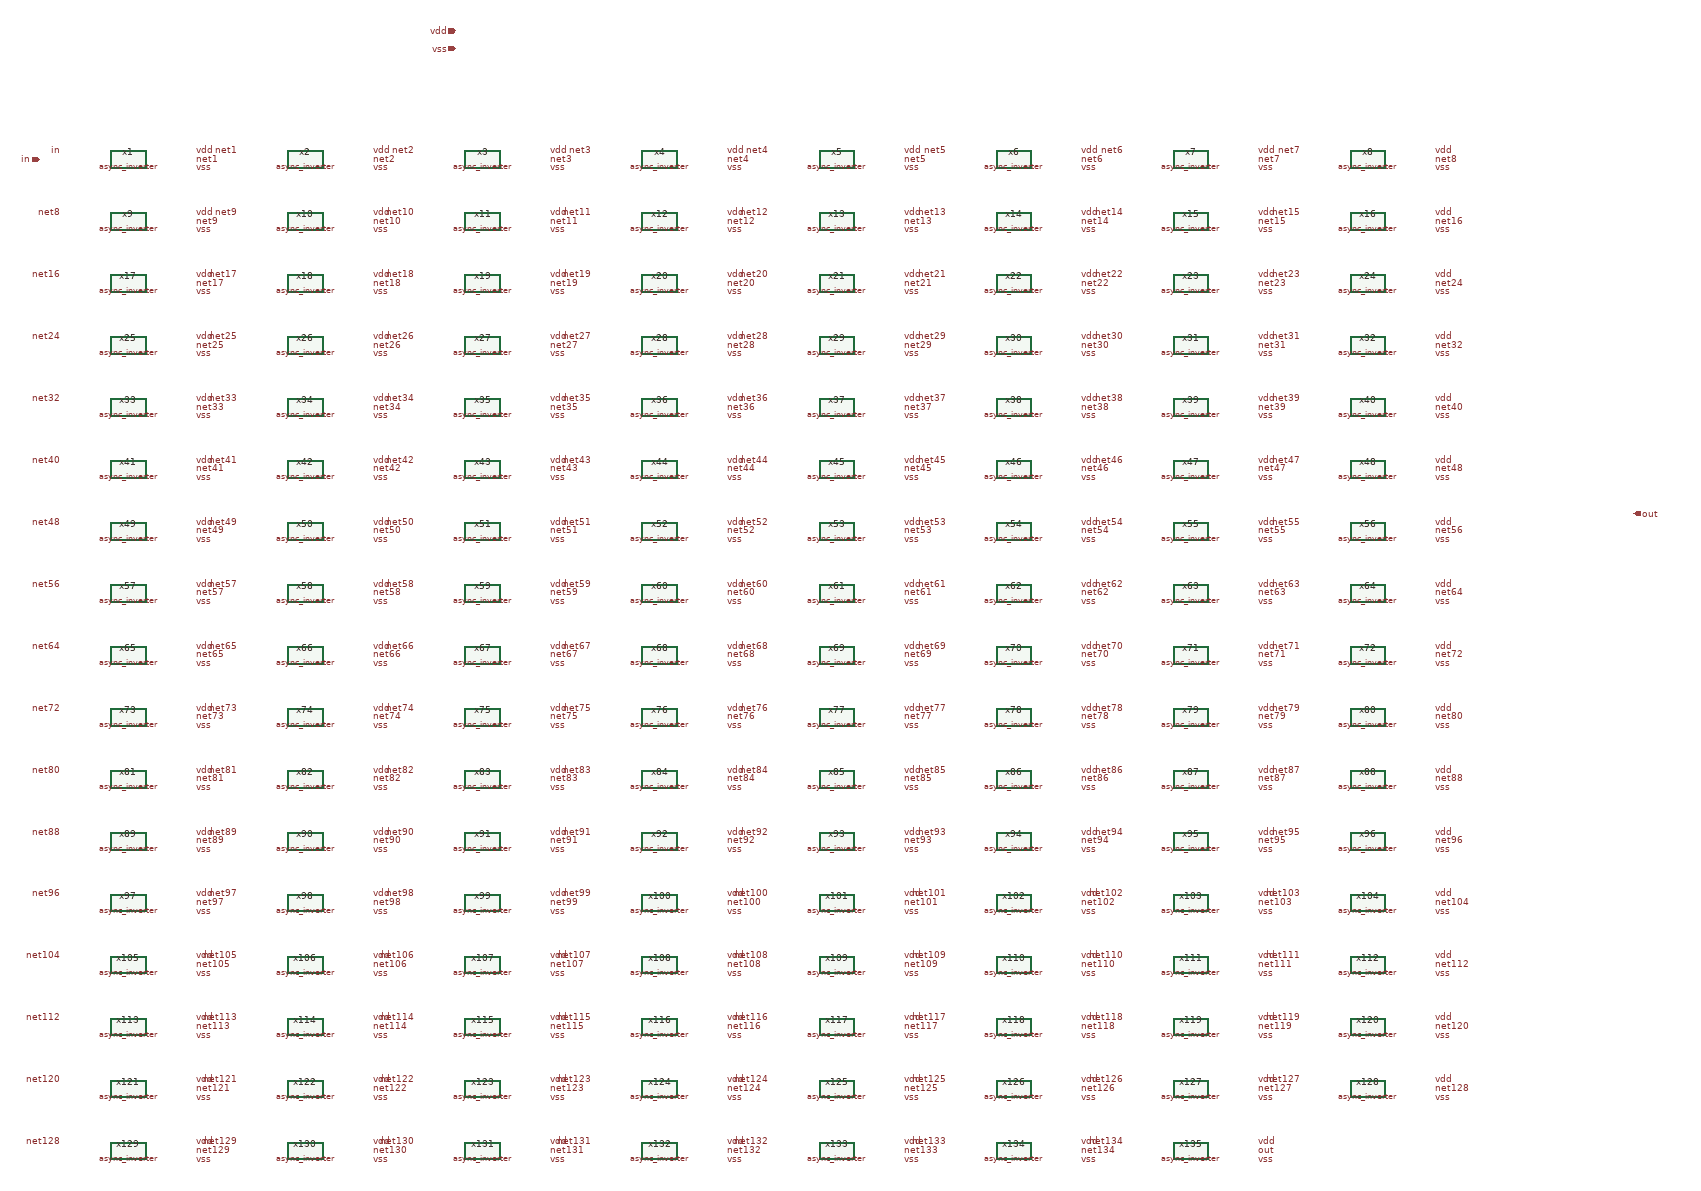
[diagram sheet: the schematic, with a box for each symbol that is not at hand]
v {xschem version=3.4.8RC file_version=1.3}
G {}
K {}
V {}
S {}
F {}
E {}
C {ipin.sym} -1600 -400 0 0 {name=p_in lab=in}
C {iopin.sym} -660 -690 0 0 {name=p_vdd lab=vdd}
C {iopin.sym} -660 -650 0 0 {name=p_vss lab=vss}
C {opin.sym} 2000 400 0 0 {name=p_out lab=out}
C {sar_adc/blocks/async_sar/async_inverter.sym} -1400 -400 0 0 {name=x1}
C {lab_wire.sym} -1550 -420 0 0 {name=l_x1_in lab=in}
C {lab_wire.sym} -1250 -400 2 0 {name=l_x1_out lab=net1}
C {lab_wire.sym} -1250 -420 2 0 {name=l_x1_vdd lab=vdd}
C {lab_wire.sym} -1250 -380 2 0 {name=l_x1_vss lab=vss}
C {sar_adc/blocks/async_sar/async_inverter.sym} -1000 -400 0 0 {name=x2}
C {lab_wire.sym} -1150 -420 0 0 {name=l_x2_in lab=net1}
C {lab_wire.sym} -850 -400 2 0 {name=l_x2_out lab=net2}
C {lab_wire.sym} -850 -420 2 0 {name=l_x2_vdd lab=vdd}
C {lab_wire.sym} -850 -380 2 0 {name=l_x2_vss lab=vss}
C {sar_adc/blocks/async_sar/async_inverter.sym} -600 -400 0 0 {name=x3}
C {lab_wire.sym} -750 -420 0 0 {name=l_x3_in lab=net2}
C {lab_wire.sym} -450 -400 2 0 {name=l_x3_out lab=net3}
C {lab_wire.sym} -450 -420 2 0 {name=l_x3_vdd lab=vdd}
C {lab_wire.sym} -450 -380 2 0 {name=l_x3_vss lab=vss}
C {sar_adc/blocks/async_sar/async_inverter.sym} -200 -400 0 0 {name=x4}
C {lab_wire.sym} -350 -420 0 0 {name=l_x4_in lab=net3}
C {lab_wire.sym} -50 -400 2 0 {name=l_x4_out lab=net4}
C {lab_wire.sym} -50 -420 2 0 {name=l_x4_vdd lab=vdd}
C {lab_wire.sym} -50 -380 2 0 {name=l_x4_vss lab=vss}
C {sar_adc/blocks/async_sar/async_inverter.sym} 200 -400 0 0 {name=x5}
C {lab_wire.sym} 50 -420 0 0 {name=l_x5_in lab=net4}
C {lab_wire.sym} 350 -400 2 0 {name=l_x5_out lab=net5}
C {lab_wire.sym} 350 -420 2 0 {name=l_x5_vdd lab=vdd}
C {lab_wire.sym} 350 -380 2 0 {name=l_x5_vss lab=vss}
C {sar_adc/blocks/async_sar/async_inverter.sym} 600 -400 0 0 {name=x6}
C {lab_wire.sym} 450 -420 0 0 {name=l_x6_in lab=net5}
C {lab_wire.sym} 750 -400 2 0 {name=l_x6_out lab=net6}
C {lab_wire.sym} 750 -420 2 0 {name=l_x6_vdd lab=vdd}
C {lab_wire.sym} 750 -380 2 0 {name=l_x6_vss lab=vss}
C {sar_adc/blocks/async_sar/async_inverter.sym} 1000 -400 0 0 {name=x7}
C {lab_wire.sym} 850 -420 0 0 {name=l_x7_in lab=net6}
C {lab_wire.sym} 1150 -400 2 0 {name=l_x7_out lab=net7}
C {lab_wire.sym} 1150 -420 2 0 {name=l_x7_vdd lab=vdd}
C {lab_wire.sym} 1150 -380 2 0 {name=l_x7_vss lab=vss}
C {sar_adc/blocks/async_sar/async_inverter.sym} 1400 -400 0 0 {name=x8}
C {lab_wire.sym} 1250 -420 0 0 {name=l_x8_in lab=net7}
C {lab_wire.sym} 1550 -400 2 0 {name=l_x8_out lab=net8}
C {lab_wire.sym} 1550 -420 2 0 {name=l_x8_vdd lab=vdd}
C {lab_wire.sym} 1550 -380 2 0 {name=l_x8_vss lab=vss}
C {sar_adc/blocks/async_sar/async_inverter.sym} -1400 -260 0 0 {name=x9}
C {lab_wire.sym} -1550 -280 0 0 {name=l_x9_in lab=net8}
C {lab_wire.sym} -1250 -260 2 0 {name=l_x9_out lab=net9}
C {lab_wire.sym} -1250 -280 2 0 {name=l_x9_vdd lab=vdd}
C {lab_wire.sym} -1250 -240 2 0 {name=l_x9_vss lab=vss}
C {sar_adc/blocks/async_sar/async_inverter.sym} -1000 -260 0 0 {name=x10}
C {lab_wire.sym} -1150 -280 0 0 {name=l_x10_in lab=net9}
C {lab_wire.sym} -850 -260 2 0 {name=l_x10_out lab=net10}
C {lab_wire.sym} -850 -280 2 0 {name=l_x10_vdd lab=vdd}
C {lab_wire.sym} -850 -240 2 0 {name=l_x10_vss lab=vss}
C {sar_adc/blocks/async_sar/async_inverter.sym} -600 -260 0 0 {name=x11}
C {lab_wire.sym} -750 -280 0 0 {name=l_x11_in lab=net10}
C {lab_wire.sym} -450 -260 2 0 {name=l_x11_out lab=net11}
C {lab_wire.sym} -450 -280 2 0 {name=l_x11_vdd lab=vdd}
C {lab_wire.sym} -450 -240 2 0 {name=l_x11_vss lab=vss}
C {sar_adc/blocks/async_sar/async_inverter.sym} -200 -260 0 0 {name=x12}
C {lab_wire.sym} -350 -280 0 0 {name=l_x12_in lab=net11}
C {lab_wire.sym} -50 -260 2 0 {name=l_x12_out lab=net12}
C {lab_wire.sym} -50 -280 2 0 {name=l_x12_vdd lab=vdd}
C {lab_wire.sym} -50 -240 2 0 {name=l_x12_vss lab=vss}
C {sar_adc/blocks/async_sar/async_inverter.sym} 200 -260 0 0 {name=x13}
C {lab_wire.sym} 50 -280 0 0 {name=l_x13_in lab=net12}
C {lab_wire.sym} 350 -260 2 0 {name=l_x13_out lab=net13}
C {lab_wire.sym} 350 -280 2 0 {name=l_x13_vdd lab=vdd}
C {lab_wire.sym} 350 -240 2 0 {name=l_x13_vss lab=vss}
C {sar_adc/blocks/async_sar/async_inverter.sym} 600 -260 0 0 {name=x14}
C {lab_wire.sym} 450 -280 0 0 {name=l_x14_in lab=net13}
C {lab_wire.sym} 750 -260 2 0 {name=l_x14_out lab=net14}
C {lab_wire.sym} 750 -280 2 0 {name=l_x14_vdd lab=vdd}
C {lab_wire.sym} 750 -240 2 0 {name=l_x14_vss lab=vss}
C {sar_adc/blocks/async_sar/async_inverter.sym} 1000 -260 0 0 {name=x15}
C {lab_wire.sym} 850 -280 0 0 {name=l_x15_in lab=net14}
C {lab_wire.sym} 1150 -260 2 0 {name=l_x15_out lab=net15}
C {lab_wire.sym} 1150 -280 2 0 {name=l_x15_vdd lab=vdd}
C {lab_wire.sym} 1150 -240 2 0 {name=l_x15_vss lab=vss}
C {sar_adc/blocks/async_sar/async_inverter.sym} 1400 -260 0 0 {name=x16}
C {lab_wire.sym} 1250 -280 0 0 {name=l_x16_in lab=net15}
C {lab_wire.sym} 1550 -260 2 0 {name=l_x16_out lab=net16}
C {lab_wire.sym} 1550 -280 2 0 {name=l_x16_vdd lab=vdd}
C {lab_wire.sym} 1550 -240 2 0 {name=l_x16_vss lab=vss}
C {sar_adc/blocks/async_sar/async_inverter.sym} -1400 -120 0 0 {name=x17}
C {lab_wire.sym} -1550 -140 0 0 {name=l_x17_in lab=net16}
C {lab_wire.sym} -1250 -120 2 0 {name=l_x17_out lab=net17}
C {lab_wire.sym} -1250 -140 2 0 {name=l_x17_vdd lab=vdd}
C {lab_wire.sym} -1250 -100 2 0 {name=l_x17_vss lab=vss}
C {sar_adc/blocks/async_sar/async_inverter.sym} -1000 -120 0 0 {name=x18}
C {lab_wire.sym} -1150 -140 0 0 {name=l_x18_in lab=net17}
C {lab_wire.sym} -850 -120 2 0 {name=l_x18_out lab=net18}
C {lab_wire.sym} -850 -140 2 0 {name=l_x18_vdd lab=vdd}
C {lab_wire.sym} -850 -100 2 0 {name=l_x18_vss lab=vss}
C {sar_adc/blocks/async_sar/async_inverter.sym} -600 -120 0 0 {name=x19}
C {lab_wire.sym} -750 -140 0 0 {name=l_x19_in lab=net18}
C {lab_wire.sym} -450 -120 2 0 {name=l_x19_out lab=net19}
C {lab_wire.sym} -450 -140 2 0 {name=l_x19_vdd lab=vdd}
C {lab_wire.sym} -450 -100 2 0 {name=l_x19_vss lab=vss}
C {sar_adc/blocks/async_sar/async_inverter.sym} -200 -120 0 0 {name=x20}
C {lab_wire.sym} -350 -140 0 0 {name=l_x20_in lab=net19}
C {lab_wire.sym} -50 -120 2 0 {name=l_x20_out lab=net20}
C {lab_wire.sym} -50 -140 2 0 {name=l_x20_vdd lab=vdd}
C {lab_wire.sym} -50 -100 2 0 {name=l_x20_vss lab=vss}
C {sar_adc/blocks/async_sar/async_inverter.sym} 200 -120 0 0 {name=x21}
C {lab_wire.sym} 50 -140 0 0 {name=l_x21_in lab=net20}
C {lab_wire.sym} 350 -120 2 0 {name=l_x21_out lab=net21}
C {lab_wire.sym} 350 -140 2 0 {name=l_x21_vdd lab=vdd}
C {lab_wire.sym} 350 -100 2 0 {name=l_x21_vss lab=vss}
C {sar_adc/blocks/async_sar/async_inverter.sym} 600 -120 0 0 {name=x22}
C {lab_wire.sym} 450 -140 0 0 {name=l_x22_in lab=net21}
C {lab_wire.sym} 750 -120 2 0 {name=l_x22_out lab=net22}
C {lab_wire.sym} 750 -140 2 0 {name=l_x22_vdd lab=vdd}
C {lab_wire.sym} 750 -100 2 0 {name=l_x22_vss lab=vss}
C {sar_adc/blocks/async_sar/async_inverter.sym} 1000 -120 0 0 {name=x23}
C {lab_wire.sym} 850 -140 0 0 {name=l_x23_in lab=net22}
C {lab_wire.sym} 1150 -120 2 0 {name=l_x23_out lab=net23}
C {lab_wire.sym} 1150 -140 2 0 {name=l_x23_vdd lab=vdd}
C {lab_wire.sym} 1150 -100 2 0 {name=l_x23_vss lab=vss}
C {sar_adc/blocks/async_sar/async_inverter.sym} 1400 -120 0 0 {name=x24}
C {lab_wire.sym} 1250 -140 0 0 {name=l_x24_in lab=net23}
C {lab_wire.sym} 1550 -120 2 0 {name=l_x24_out lab=net24}
C {lab_wire.sym} 1550 -140 2 0 {name=l_x24_vdd lab=vdd}
C {lab_wire.sym} 1550 -100 2 0 {name=l_x24_vss lab=vss}
C {sar_adc/blocks/async_sar/async_inverter.sym} -1400 20 0 0 {name=x25}
C {lab_wire.sym} -1550 0 0 0 {name=l_x25_in lab=net24}
C {lab_wire.sym} -1250 20 2 0 {name=l_x25_out lab=net25}
C {lab_wire.sym} -1250 0 2 0 {name=l_x25_vdd lab=vdd}
C {lab_wire.sym} -1250 40 2 0 {name=l_x25_vss lab=vss}
C {sar_adc/blocks/async_sar/async_inverter.sym} -1000 20 0 0 {name=x26}
C {lab_wire.sym} -1150 0 0 0 {name=l_x26_in lab=net25}
C {lab_wire.sym} -850 20 2 0 {name=l_x26_out lab=net26}
C {lab_wire.sym} -850 0 2 0 {name=l_x26_vdd lab=vdd}
C {lab_wire.sym} -850 40 2 0 {name=l_x26_vss lab=vss}
C {sar_adc/blocks/async_sar/async_inverter.sym} -600 20 0 0 {name=x27}
C {lab_wire.sym} -750 0 0 0 {name=l_x27_in lab=net26}
C {lab_wire.sym} -450 20 2 0 {name=l_x27_out lab=net27}
C {lab_wire.sym} -450 0 2 0 {name=l_x27_vdd lab=vdd}
C {lab_wire.sym} -450 40 2 0 {name=l_x27_vss lab=vss}
C {sar_adc/blocks/async_sar/async_inverter.sym} -200 20 0 0 {name=x28}
C {lab_wire.sym} -350 0 0 0 {name=l_x28_in lab=net27}
C {lab_wire.sym} -50 20 2 0 {name=l_x28_out lab=net28}
C {lab_wire.sym} -50 0 2 0 {name=l_x28_vdd lab=vdd}
C {lab_wire.sym} -50 40 2 0 {name=l_x28_vss lab=vss}
C {sar_adc/blocks/async_sar/async_inverter.sym} 200 20 0 0 {name=x29}
C {lab_wire.sym} 50 0 0 0 {name=l_x29_in lab=net28}
C {lab_wire.sym} 350 20 2 0 {name=l_x29_out lab=net29}
C {lab_wire.sym} 350 0 2 0 {name=l_x29_vdd lab=vdd}
C {lab_wire.sym} 350 40 2 0 {name=l_x29_vss lab=vss}
C {sar_adc/blocks/async_sar/async_inverter.sym} 600 20 0 0 {name=x30}
C {lab_wire.sym} 450 0 0 0 {name=l_x30_in lab=net29}
C {lab_wire.sym} 750 20 2 0 {name=l_x30_out lab=net30}
C {lab_wire.sym} 750 0 2 0 {name=l_x30_vdd lab=vdd}
C {lab_wire.sym} 750 40 2 0 {name=l_x30_vss lab=vss}
C {sar_adc/blocks/async_sar/async_inverter.sym} 1000 20 0 0 {name=x31}
C {lab_wire.sym} 850 0 0 0 {name=l_x31_in lab=net30}
C {lab_wire.sym} 1150 20 2 0 {name=l_x31_out lab=net31}
C {lab_wire.sym} 1150 0 2 0 {name=l_x31_vdd lab=vdd}
C {lab_wire.sym} 1150 40 2 0 {name=l_x31_vss lab=vss}
C {sar_adc/blocks/async_sar/async_inverter.sym} 1400 20 0 0 {name=x32}
C {lab_wire.sym} 1250 0 0 0 {name=l_x32_in lab=net31}
C {lab_wire.sym} 1550 20 2 0 {name=l_x32_out lab=net32}
C {lab_wire.sym} 1550 0 2 0 {name=l_x32_vdd lab=vdd}
C {lab_wire.sym} 1550 40 2 0 {name=l_x32_vss lab=vss}
C {sar_adc/blocks/async_sar/async_inverter.sym} -1400 160 0 0 {name=x33}
C {lab_wire.sym} -1550 140 0 0 {name=l_x33_in lab=net32}
C {lab_wire.sym} -1250 160 2 0 {name=l_x33_out lab=net33}
C {lab_wire.sym} -1250 140 2 0 {name=l_x33_vdd lab=vdd}
C {lab_wire.sym} -1250 180 2 0 {name=l_x33_vss lab=vss}
C {sar_adc/blocks/async_sar/async_inverter.sym} -1000 160 0 0 {name=x34}
C {lab_wire.sym} -1150 140 0 0 {name=l_x34_in lab=net33}
C {lab_wire.sym} -850 160 2 0 {name=l_x34_out lab=net34}
C {lab_wire.sym} -850 140 2 0 {name=l_x34_vdd lab=vdd}
C {lab_wire.sym} -850 180 2 0 {name=l_x34_vss lab=vss}
C {sar_adc/blocks/async_sar/async_inverter.sym} -600 160 0 0 {name=x35}
C {lab_wire.sym} -750 140 0 0 {name=l_x35_in lab=net34}
C {lab_wire.sym} -450 160 2 0 {name=l_x35_out lab=net35}
C {lab_wire.sym} -450 140 2 0 {name=l_x35_vdd lab=vdd}
C {lab_wire.sym} -450 180 2 0 {name=l_x35_vss lab=vss}
C {sar_adc/blocks/async_sar/async_inverter.sym} -200 160 0 0 {name=x36}
C {lab_wire.sym} -350 140 0 0 {name=l_x36_in lab=net35}
C {lab_wire.sym} -50 160 2 0 {name=l_x36_out lab=net36}
C {lab_wire.sym} -50 140 2 0 {name=l_x36_vdd lab=vdd}
C {lab_wire.sym} -50 180 2 0 {name=l_x36_vss lab=vss}
C {sar_adc/blocks/async_sar/async_inverter.sym} 200 160 0 0 {name=x37}
C {lab_wire.sym} 50 140 0 0 {name=l_x37_in lab=net36}
C {lab_wire.sym} 350 160 2 0 {name=l_x37_out lab=net37}
C {lab_wire.sym} 350 140 2 0 {name=l_x37_vdd lab=vdd}
C {lab_wire.sym} 350 180 2 0 {name=l_x37_vss lab=vss}
C {sar_adc/blocks/async_sar/async_inverter.sym} 600 160 0 0 {name=x38}
C {lab_wire.sym} 450 140 0 0 {name=l_x38_in lab=net37}
C {lab_wire.sym} 750 160 2 0 {name=l_x38_out lab=net38}
C {lab_wire.sym} 750 140 2 0 {name=l_x38_vdd lab=vdd}
C {lab_wire.sym} 750 180 2 0 {name=l_x38_vss lab=vss}
C {sar_adc/blocks/async_sar/async_inverter.sym} 1000 160 0 0 {name=x39}
C {lab_wire.sym} 850 140 0 0 {name=l_x39_in lab=net38}
C {lab_wire.sym} 1150 160 2 0 {name=l_x39_out lab=net39}
C {lab_wire.sym} 1150 140 2 0 {name=l_x39_vdd lab=vdd}
C {lab_wire.sym} 1150 180 2 0 {name=l_x39_vss lab=vss}
C {sar_adc/blocks/async_sar/async_inverter.sym} 1400 160 0 0 {name=x40}
C {lab_wire.sym} 1250 140 0 0 {name=l_x40_in lab=net39}
C {lab_wire.sym} 1550 160 2 0 {name=l_x40_out lab=net40}
C {lab_wire.sym} 1550 140 2 0 {name=l_x40_vdd lab=vdd}
C {lab_wire.sym} 1550 180 2 0 {name=l_x40_vss lab=vss}
C {sar_adc/blocks/async_sar/async_inverter.sym} -1400 300 0 0 {name=x41}
C {lab_wire.sym} -1550 280 0 0 {name=l_x41_in lab=net40}
C {lab_wire.sym} -1250 300 2 0 {name=l_x41_out lab=net41}
C {lab_wire.sym} -1250 280 2 0 {name=l_x41_vdd lab=vdd}
C {lab_wire.sym} -1250 320 2 0 {name=l_x41_vss lab=vss}
C {sar_adc/blocks/async_sar/async_inverter.sym} -1000 300 0 0 {name=x42}
C {lab_wire.sym} -1150 280 0 0 {name=l_x42_in lab=net41}
C {lab_wire.sym} -850 300 2 0 {name=l_x42_out lab=net42}
C {lab_wire.sym} -850 280 2 0 {name=l_x42_vdd lab=vdd}
C {lab_wire.sym} -850 320 2 0 {name=l_x42_vss lab=vss}
C {sar_adc/blocks/async_sar/async_inverter.sym} -600 300 0 0 {name=x43}
C {lab_wire.sym} -750 280 0 0 {name=l_x43_in lab=net42}
C {lab_wire.sym} -450 300 2 0 {name=l_x43_out lab=net43}
C {lab_wire.sym} -450 280 2 0 {name=l_x43_vdd lab=vdd}
C {lab_wire.sym} -450 320 2 0 {name=l_x43_vss lab=vss}
C {sar_adc/blocks/async_sar/async_inverter.sym} -200 300 0 0 {name=x44}
C {lab_wire.sym} -350 280 0 0 {name=l_x44_in lab=net43}
C {lab_wire.sym} -50 300 2 0 {name=l_x44_out lab=net44}
C {lab_wire.sym} -50 280 2 0 {name=l_x44_vdd lab=vdd}
C {lab_wire.sym} -50 320 2 0 {name=l_x44_vss lab=vss}
C {sar_adc/blocks/async_sar/async_inverter.sym} 200 300 0 0 {name=x45}
C {lab_wire.sym} 50 280 0 0 {name=l_x45_in lab=net44}
C {lab_wire.sym} 350 300 2 0 {name=l_x45_out lab=net45}
C {lab_wire.sym} 350 280 2 0 {name=l_x45_vdd lab=vdd}
C {lab_wire.sym} 350 320 2 0 {name=l_x45_vss lab=vss}
C {sar_adc/blocks/async_sar/async_inverter.sym} 600 300 0 0 {name=x46}
C {lab_wire.sym} 450 280 0 0 {name=l_x46_in lab=net45}
C {lab_wire.sym} 750 300 2 0 {name=l_x46_out lab=net46}
C {lab_wire.sym} 750 280 2 0 {name=l_x46_vdd lab=vdd}
C {lab_wire.sym} 750 320 2 0 {name=l_x46_vss lab=vss}
C {sar_adc/blocks/async_sar/async_inverter.sym} 1000 300 0 0 {name=x47}
C {lab_wire.sym} 850 280 0 0 {name=l_x47_in lab=net46}
C {lab_wire.sym} 1150 300 2 0 {name=l_x47_out lab=net47}
C {lab_wire.sym} 1150 280 2 0 {name=l_x47_vdd lab=vdd}
C {lab_wire.sym} 1150 320 2 0 {name=l_x47_vss lab=vss}
C {sar_adc/blocks/async_sar/async_inverter.sym} 1400 300 0 0 {name=x48}
C {lab_wire.sym} 1250 280 0 0 {name=l_x48_in lab=net47}
C {lab_wire.sym} 1550 300 2 0 {name=l_x48_out lab=net48}
C {lab_wire.sym} 1550 280 2 0 {name=l_x48_vdd lab=vdd}
C {lab_wire.sym} 1550 320 2 0 {name=l_x48_vss lab=vss}
C {sar_adc/blocks/async_sar/async_inverter.sym} -1400 440 0 0 {name=x49}
C {lab_wire.sym} -1550 420 0 0 {name=l_x49_in lab=net48}
C {lab_wire.sym} -1250 440 2 0 {name=l_x49_out lab=net49}
C {lab_wire.sym} -1250 420 2 0 {name=l_x49_vdd lab=vdd}
C {lab_wire.sym} -1250 460 2 0 {name=l_x49_vss lab=vss}
C {sar_adc/blocks/async_sar/async_inverter.sym} -1000 440 0 0 {name=x50}
C {lab_wire.sym} -1150 420 0 0 {name=l_x50_in lab=net49}
C {lab_wire.sym} -850 440 2 0 {name=l_x50_out lab=net50}
C {lab_wire.sym} -850 420 2 0 {name=l_x50_vdd lab=vdd}
C {lab_wire.sym} -850 460 2 0 {name=l_x50_vss lab=vss}
C {sar_adc/blocks/async_sar/async_inverter.sym} -600 440 0 0 {name=x51}
C {lab_wire.sym} -750 420 0 0 {name=l_x51_in lab=net50}
C {lab_wire.sym} -450 440 2 0 {name=l_x51_out lab=net51}
C {lab_wire.sym} -450 420 2 0 {name=l_x51_vdd lab=vdd}
C {lab_wire.sym} -450 460 2 0 {name=l_x51_vss lab=vss}
C {sar_adc/blocks/async_sar/async_inverter.sym} -200 440 0 0 {name=x52}
C {lab_wire.sym} -350 420 0 0 {name=l_x52_in lab=net51}
C {lab_wire.sym} -50 440 2 0 {name=l_x52_out lab=net52}
C {lab_wire.sym} -50 420 2 0 {name=l_x52_vdd lab=vdd}
C {lab_wire.sym} -50 460 2 0 {name=l_x52_vss lab=vss}
C {sar_adc/blocks/async_sar/async_inverter.sym} 200 440 0 0 {name=x53}
C {lab_wire.sym} 50 420 0 0 {name=l_x53_in lab=net52}
C {lab_wire.sym} 350 440 2 0 {name=l_x53_out lab=net53}
C {lab_wire.sym} 350 420 2 0 {name=l_x53_vdd lab=vdd}
C {lab_wire.sym} 350 460 2 0 {name=l_x53_vss lab=vss}
C {sar_adc/blocks/async_sar/async_inverter.sym} 600 440 0 0 {name=x54}
C {lab_wire.sym} 450 420 0 0 {name=l_x54_in lab=net53}
C {lab_wire.sym} 750 440 2 0 {name=l_x54_out lab=net54}
C {lab_wire.sym} 750 420 2 0 {name=l_x54_vdd lab=vdd}
C {lab_wire.sym} 750 460 2 0 {name=l_x54_vss lab=vss}
C {sar_adc/blocks/async_sar/async_inverter.sym} 1000 440 0 0 {name=x55}
C {lab_wire.sym} 850 420 0 0 {name=l_x55_in lab=net54}
C {lab_wire.sym} 1150 440 2 0 {name=l_x55_out lab=net55}
C {lab_wire.sym} 1150 420 2 0 {name=l_x55_vdd lab=vdd}
C {lab_wire.sym} 1150 460 2 0 {name=l_x55_vss lab=vss}
C {sar_adc/blocks/async_sar/async_inverter.sym} 1400 440 0 0 {name=x56}
C {lab_wire.sym} 1250 420 0 0 {name=l_x56_in lab=net55}
C {lab_wire.sym} 1550 440 2 0 {name=l_x56_out lab=net56}
C {lab_wire.sym} 1550 420 2 0 {name=l_x56_vdd lab=vdd}
C {lab_wire.sym} 1550 460 2 0 {name=l_x56_vss lab=vss}
C {sar_adc/blocks/async_sar/async_inverter.sym} -1400 580 0 0 {name=x57}
C {lab_wire.sym} -1550 560 0 0 {name=l_x57_in lab=net56}
C {lab_wire.sym} -1250 580 2 0 {name=l_x57_out lab=net57}
C {lab_wire.sym} -1250 560 2 0 {name=l_x57_vdd lab=vdd}
C {lab_wire.sym} -1250 600 2 0 {name=l_x57_vss lab=vss}
C {sar_adc/blocks/async_sar/async_inverter.sym} -1000 580 0 0 {name=x58}
C {lab_wire.sym} -1150 560 0 0 {name=l_x58_in lab=net57}
C {lab_wire.sym} -850 580 2 0 {name=l_x58_out lab=net58}
C {lab_wire.sym} -850 560 2 0 {name=l_x58_vdd lab=vdd}
C {lab_wire.sym} -850 600 2 0 {name=l_x58_vss lab=vss}
C {sar_adc/blocks/async_sar/async_inverter.sym} -600 580 0 0 {name=x59}
C {lab_wire.sym} -750 560 0 0 {name=l_x59_in lab=net58}
C {lab_wire.sym} -450 580 2 0 {name=l_x59_out lab=net59}
C {lab_wire.sym} -450 560 2 0 {name=l_x59_vdd lab=vdd}
C {lab_wire.sym} -450 600 2 0 {name=l_x59_vss lab=vss}
C {sar_adc/blocks/async_sar/async_inverter.sym} -200 580 0 0 {name=x60}
C {lab_wire.sym} -350 560 0 0 {name=l_x60_in lab=net59}
C {lab_wire.sym} -50 580 2 0 {name=l_x60_out lab=net60}
C {lab_wire.sym} -50 560 2 0 {name=l_x60_vdd lab=vdd}
C {lab_wire.sym} -50 600 2 0 {name=l_x60_vss lab=vss}
C {sar_adc/blocks/async_sar/async_inverter.sym} 200 580 0 0 {name=x61}
C {lab_wire.sym} 50 560 0 0 {name=l_x61_in lab=net60}
C {lab_wire.sym} 350 580 2 0 {name=l_x61_out lab=net61}
C {lab_wire.sym} 350 560 2 0 {name=l_x61_vdd lab=vdd}
C {lab_wire.sym} 350 600 2 0 {name=l_x61_vss lab=vss}
C {sar_adc/blocks/async_sar/async_inverter.sym} 600 580 0 0 {name=x62}
C {lab_wire.sym} 450 560 0 0 {name=l_x62_in lab=net61}
C {lab_wire.sym} 750 580 2 0 {name=l_x62_out lab=net62}
C {lab_wire.sym} 750 560 2 0 {name=l_x62_vdd lab=vdd}
C {lab_wire.sym} 750 600 2 0 {name=l_x62_vss lab=vss}
C {sar_adc/blocks/async_sar/async_inverter.sym} 1000 580 0 0 {name=x63}
C {lab_wire.sym} 850 560 0 0 {name=l_x63_in lab=net62}
C {lab_wire.sym} 1150 580 2 0 {name=l_x63_out lab=net63}
C {lab_wire.sym} 1150 560 2 0 {name=l_x63_vdd lab=vdd}
C {lab_wire.sym} 1150 600 2 0 {name=l_x63_vss lab=vss}
C {sar_adc/blocks/async_sar/async_inverter.sym} 1400 580 0 0 {name=x64}
C {lab_wire.sym} 1250 560 0 0 {name=l_x64_in lab=net63}
C {lab_wire.sym} 1550 580 2 0 {name=l_x64_out lab=net64}
C {lab_wire.sym} 1550 560 2 0 {name=l_x64_vdd lab=vdd}
C {lab_wire.sym} 1550 600 2 0 {name=l_x64_vss lab=vss}
C {sar_adc/blocks/async_sar/async_inverter.sym} -1400 720 0 0 {name=x65}
C {lab_wire.sym} -1550 700 0 0 {name=l_x65_in lab=net64}
C {lab_wire.sym} -1250 720 2 0 {name=l_x65_out lab=net65}
C {lab_wire.sym} -1250 700 2 0 {name=l_x65_vdd lab=vdd}
C {lab_wire.sym} -1250 740 2 0 {name=l_x65_vss lab=vss}
C {sar_adc/blocks/async_sar/async_inverter.sym} -1000 720 0 0 {name=x66}
C {lab_wire.sym} -1150 700 0 0 {name=l_x66_in lab=net65}
C {lab_wire.sym} -850 720 2 0 {name=l_x66_out lab=net66}
C {lab_wire.sym} -850 700 2 0 {name=l_x66_vdd lab=vdd}
C {lab_wire.sym} -850 740 2 0 {name=l_x66_vss lab=vss}
C {sar_adc/blocks/async_sar/async_inverter.sym} -600 720 0 0 {name=x67}
C {lab_wire.sym} -750 700 0 0 {name=l_x67_in lab=net66}
C {lab_wire.sym} -450 720 2 0 {name=l_x67_out lab=net67}
C {lab_wire.sym} -450 700 2 0 {name=l_x67_vdd lab=vdd}
C {lab_wire.sym} -450 740 2 0 {name=l_x67_vss lab=vss}
C {sar_adc/blocks/async_sar/async_inverter.sym} -200 720 0 0 {name=x68}
C {lab_wire.sym} -350 700 0 0 {name=l_x68_in lab=net67}
C {lab_wire.sym} -50 720 2 0 {name=l_x68_out lab=net68}
C {lab_wire.sym} -50 700 2 0 {name=l_x68_vdd lab=vdd}
C {lab_wire.sym} -50 740 2 0 {name=l_x68_vss lab=vss}
C {sar_adc/blocks/async_sar/async_inverter.sym} 200 720 0 0 {name=x69}
C {lab_wire.sym} 50 700 0 0 {name=l_x69_in lab=net68}
C {lab_wire.sym} 350 720 2 0 {name=l_x69_out lab=net69}
C {lab_wire.sym} 350 700 2 0 {name=l_x69_vdd lab=vdd}
C {lab_wire.sym} 350 740 2 0 {name=l_x69_vss lab=vss}
C {sar_adc/blocks/async_sar/async_inverter.sym} 600 720 0 0 {name=x70}
C {lab_wire.sym} 450 700 0 0 {name=l_x70_in lab=net69}
C {lab_wire.sym} 750 720 2 0 {name=l_x70_out lab=net70}
C {lab_wire.sym} 750 700 2 0 {name=l_x70_vdd lab=vdd}
C {lab_wire.sym} 750 740 2 0 {name=l_x70_vss lab=vss}
C {sar_adc/blocks/async_sar/async_inverter.sym} 1000 720 0 0 {name=x71}
C {lab_wire.sym} 850 700 0 0 {name=l_x71_in lab=net70}
C {lab_wire.sym} 1150 720 2 0 {name=l_x71_out lab=net71}
C {lab_wire.sym} 1150 700 2 0 {name=l_x71_vdd lab=vdd}
C {lab_wire.sym} 1150 740 2 0 {name=l_x71_vss lab=vss}
C {sar_adc/blocks/async_sar/async_inverter.sym} 1400 720 0 0 {name=x72}
C {lab_wire.sym} 1250 700 0 0 {name=l_x72_in lab=net71}
C {lab_wire.sym} 1550 720 2 0 {name=l_x72_out lab=net72}
C {lab_wire.sym} 1550 700 2 0 {name=l_x72_vdd lab=vdd}
C {lab_wire.sym} 1550 740 2 0 {name=l_x72_vss lab=vss}
C {sar_adc/blocks/async_sar/async_inverter.sym} -1400 860 0 0 {name=x73}
C {lab_wire.sym} -1550 840 0 0 {name=l_x73_in lab=net72}
C {lab_wire.sym} -1250 860 2 0 {name=l_x73_out lab=net73}
C {lab_wire.sym} -1250 840 2 0 {name=l_x73_vdd lab=vdd}
C {lab_wire.sym} -1250 880 2 0 {name=l_x73_vss lab=vss}
C {sar_adc/blocks/async_sar/async_inverter.sym} -1000 860 0 0 {name=x74}
C {lab_wire.sym} -1150 840 0 0 {name=l_x74_in lab=net73}
C {lab_wire.sym} -850 860 2 0 {name=l_x74_out lab=net74}
C {lab_wire.sym} -850 840 2 0 {name=l_x74_vdd lab=vdd}
C {lab_wire.sym} -850 880 2 0 {name=l_x74_vss lab=vss}
C {sar_adc/blocks/async_sar/async_inverter.sym} -600 860 0 0 {name=x75}
C {lab_wire.sym} -750 840 0 0 {name=l_x75_in lab=net74}
C {lab_wire.sym} -450 860 2 0 {name=l_x75_out lab=net75}
C {lab_wire.sym} -450 840 2 0 {name=l_x75_vdd lab=vdd}
C {lab_wire.sym} -450 880 2 0 {name=l_x75_vss lab=vss}
C {sar_adc/blocks/async_sar/async_inverter.sym} -200 860 0 0 {name=x76}
C {lab_wire.sym} -350 840 0 0 {name=l_x76_in lab=net75}
C {lab_wire.sym} -50 860 2 0 {name=l_x76_out lab=net76}
C {lab_wire.sym} -50 840 2 0 {name=l_x76_vdd lab=vdd}
C {lab_wire.sym} -50 880 2 0 {name=l_x76_vss lab=vss}
C {sar_adc/blocks/async_sar/async_inverter.sym} 200 860 0 0 {name=x77}
C {lab_wire.sym} 50 840 0 0 {name=l_x77_in lab=net76}
C {lab_wire.sym} 350 860 2 0 {name=l_x77_out lab=net77}
C {lab_wire.sym} 350 840 2 0 {name=l_x77_vdd lab=vdd}
C {lab_wire.sym} 350 880 2 0 {name=l_x77_vss lab=vss}
C {sar_adc/blocks/async_sar/async_inverter.sym} 600 860 0 0 {name=x78}
C {lab_wire.sym} 450 840 0 0 {name=l_x78_in lab=net77}
C {lab_wire.sym} 750 860 2 0 {name=l_x78_out lab=net78}
C {lab_wire.sym} 750 840 2 0 {name=l_x78_vdd lab=vdd}
C {lab_wire.sym} 750 880 2 0 {name=l_x78_vss lab=vss}
C {sar_adc/blocks/async_sar/async_inverter.sym} 1000 860 0 0 {name=x79}
C {lab_wire.sym} 850 840 0 0 {name=l_x79_in lab=net78}
C {lab_wire.sym} 1150 860 2 0 {name=l_x79_out lab=net79}
C {lab_wire.sym} 1150 840 2 0 {name=l_x79_vdd lab=vdd}
C {lab_wire.sym} 1150 880 2 0 {name=l_x79_vss lab=vss}
C {sar_adc/blocks/async_sar/async_inverter.sym} 1400 860 0 0 {name=x80}
C {lab_wire.sym} 1250 840 0 0 {name=l_x80_in lab=net79}
C {lab_wire.sym} 1550 860 2 0 {name=l_x80_out lab=net80}
C {lab_wire.sym} 1550 840 2 0 {name=l_x80_vdd lab=vdd}
C {lab_wire.sym} 1550 880 2 0 {name=l_x80_vss lab=vss}
C {sar_adc/blocks/async_sar/async_inverter.sym} -1400 1000 0 0 {name=x81}
C {lab_wire.sym} -1550 980 0 0 {name=l_x81_in lab=net80}
C {lab_wire.sym} -1250 1000 2 0 {name=l_x81_out lab=net81}
C {lab_wire.sym} -1250 980 2 0 {name=l_x81_vdd lab=vdd}
C {lab_wire.sym} -1250 1020 2 0 {name=l_x81_vss lab=vss}
C {sar_adc/blocks/async_sar/async_inverter.sym} -1000 1000 0 0 {name=x82}
C {lab_wire.sym} -1150 980 0 0 {name=l_x82_in lab=net81}
C {lab_wire.sym} -850 1000 2 0 {name=l_x82_out lab=net82}
C {lab_wire.sym} -850 980 2 0 {name=l_x82_vdd lab=vdd}
C {lab_wire.sym} -850 1020 2 0 {name=l_x82_vss lab=vss}
C {sar_adc/blocks/async_sar/async_inverter.sym} -600 1000 0 0 {name=x83}
C {lab_wire.sym} -750 980 0 0 {name=l_x83_in lab=net82}
C {lab_wire.sym} -450 1000 2 0 {name=l_x83_out lab=net83}
C {lab_wire.sym} -450 980 2 0 {name=l_x83_vdd lab=vdd}
C {lab_wire.sym} -450 1020 2 0 {name=l_x83_vss lab=vss}
C {sar_adc/blocks/async_sar/async_inverter.sym} -200 1000 0 0 {name=x84}
C {lab_wire.sym} -350 980 0 0 {name=l_x84_in lab=net83}
C {lab_wire.sym} -50 1000 2 0 {name=l_x84_out lab=net84}
C {lab_wire.sym} -50 980 2 0 {name=l_x84_vdd lab=vdd}
C {lab_wire.sym} -50 1020 2 0 {name=l_x84_vss lab=vss}
C {sar_adc/blocks/async_sar/async_inverter.sym} 200 1000 0 0 {name=x85}
C {lab_wire.sym} 50 980 0 0 {name=l_x85_in lab=net84}
C {lab_wire.sym} 350 1000 2 0 {name=l_x85_out lab=net85}
C {lab_wire.sym} 350 980 2 0 {name=l_x85_vdd lab=vdd}
C {lab_wire.sym} 350 1020 2 0 {name=l_x85_vss lab=vss}
C {sar_adc/blocks/async_sar/async_inverter.sym} 600 1000 0 0 {name=x86}
C {lab_wire.sym} 450 980 0 0 {name=l_x86_in lab=net85}
C {lab_wire.sym} 750 1000 2 0 {name=l_x86_out lab=net86}
C {lab_wire.sym} 750 980 2 0 {name=l_x86_vdd lab=vdd}
C {lab_wire.sym} 750 1020 2 0 {name=l_x86_vss lab=vss}
C {sar_adc/blocks/async_sar/async_inverter.sym} 1000 1000 0 0 {name=x87}
C {lab_wire.sym} 850 980 0 0 {name=l_x87_in lab=net86}
C {lab_wire.sym} 1150 1000 2 0 {name=l_x87_out lab=net87}
C {lab_wire.sym} 1150 980 2 0 {name=l_x87_vdd lab=vdd}
C {lab_wire.sym} 1150 1020 2 0 {name=l_x87_vss lab=vss}
C {sar_adc/blocks/async_sar/async_inverter.sym} 1400 1000 0 0 {name=x88}
C {lab_wire.sym} 1250 980 0 0 {name=l_x88_in lab=net87}
C {lab_wire.sym} 1550 1000 2 0 {name=l_x88_out lab=net88}
C {lab_wire.sym} 1550 980 2 0 {name=l_x88_vdd lab=vdd}
C {lab_wire.sym} 1550 1020 2 0 {name=l_x88_vss lab=vss}
C {sar_adc/blocks/async_sar/async_inverter.sym} -1400 1140 0 0 {name=x89}
C {lab_wire.sym} -1550 1120 0 0 {name=l_x89_in lab=net88}
C {lab_wire.sym} -1250 1140 2 0 {name=l_x89_out lab=net89}
C {lab_wire.sym} -1250 1120 2 0 {name=l_x89_vdd lab=vdd}
C {lab_wire.sym} -1250 1160 2 0 {name=l_x89_vss lab=vss}
C {sar_adc/blocks/async_sar/async_inverter.sym} -1000 1140 0 0 {name=x90}
C {lab_wire.sym} -1150 1120 0 0 {name=l_x90_in lab=net89}
C {lab_wire.sym} -850 1140 2 0 {name=l_x90_out lab=net90}
C {lab_wire.sym} -850 1120 2 0 {name=l_x90_vdd lab=vdd}
C {lab_wire.sym} -850 1160 2 0 {name=l_x90_vss lab=vss}
C {sar_adc/blocks/async_sar/async_inverter.sym} -600 1140 0 0 {name=x91}
C {lab_wire.sym} -750 1120 0 0 {name=l_x91_in lab=net90}
C {lab_wire.sym} -450 1140 2 0 {name=l_x91_out lab=net91}
C {lab_wire.sym} -450 1120 2 0 {name=l_x91_vdd lab=vdd}
C {lab_wire.sym} -450 1160 2 0 {name=l_x91_vss lab=vss}
C {sar_adc/blocks/async_sar/async_inverter.sym} -200 1140 0 0 {name=x92}
C {lab_wire.sym} -350 1120 0 0 {name=l_x92_in lab=net91}
C {lab_wire.sym} -50 1140 2 0 {name=l_x92_out lab=net92}
C {lab_wire.sym} -50 1120 2 0 {name=l_x92_vdd lab=vdd}
C {lab_wire.sym} -50 1160 2 0 {name=l_x92_vss lab=vss}
C {sar_adc/blocks/async_sar/async_inverter.sym} 200 1140 0 0 {name=x93}
C {lab_wire.sym} 50 1120 0 0 {name=l_x93_in lab=net92}
C {lab_wire.sym} 350 1140 2 0 {name=l_x93_out lab=net93}
C {lab_wire.sym} 350 1120 2 0 {name=l_x93_vdd lab=vdd}
C {lab_wire.sym} 350 1160 2 0 {name=l_x93_vss lab=vss}
C {sar_adc/blocks/async_sar/async_inverter.sym} 600 1140 0 0 {name=x94}
C {lab_wire.sym} 450 1120 0 0 {name=l_x94_in lab=net93}
C {lab_wire.sym} 750 1140 2 0 {name=l_x94_out lab=net94}
C {lab_wire.sym} 750 1120 2 0 {name=l_x94_vdd lab=vdd}
C {lab_wire.sym} 750 1160 2 0 {name=l_x94_vss lab=vss}
C {sar_adc/blocks/async_sar/async_inverter.sym} 1000 1140 0 0 {name=x95}
C {lab_wire.sym} 850 1120 0 0 {name=l_x95_in lab=net94}
C {lab_wire.sym} 1150 1140 2 0 {name=l_x95_out lab=net95}
C {lab_wire.sym} 1150 1120 2 0 {name=l_x95_vdd lab=vdd}
C {lab_wire.sym} 1150 1160 2 0 {name=l_x95_vss lab=vss}
C {sar_adc/blocks/async_sar/async_inverter.sym} 1400 1140 0 0 {name=x96}
C {lab_wire.sym} 1250 1120 0 0 {name=l_x96_in lab=net95}
C {lab_wire.sym} 1550 1140 2 0 {name=l_x96_out lab=net96}
C {lab_wire.sym} 1550 1120 2 0 {name=l_x96_vdd lab=vdd}
C {lab_wire.sym} 1550 1160 2 0 {name=l_x96_vss lab=vss}
C {sar_adc/blocks/async_sar/async_inverter.sym} -1400 1280 0 0 {name=x97}
C {lab_wire.sym} -1550 1260 0 0 {name=l_x97_in lab=net96}
C {lab_wire.sym} -1250 1280 2 0 {name=l_x97_out lab=net97}
C {lab_wire.sym} -1250 1260 2 0 {name=l_x97_vdd lab=vdd}
C {lab_wire.sym} -1250 1300 2 0 {name=l_x97_vss lab=vss}
C {sar_adc/blocks/async_sar/async_inverter.sym} -1000 1280 0 0 {name=x98}
C {lab_wire.sym} -1150 1260 0 0 {name=l_x98_in lab=net97}
C {lab_wire.sym} -850 1280 2 0 {name=l_x98_out lab=net98}
C {lab_wire.sym} -850 1260 2 0 {name=l_x98_vdd lab=vdd}
C {lab_wire.sym} -850 1300 2 0 {name=l_x98_vss lab=vss}
C {sar_adc/blocks/async_sar/async_inverter.sym} -600 1280 0 0 {name=x99}
C {lab_wire.sym} -750 1260 0 0 {name=l_x99_in lab=net98}
C {lab_wire.sym} -450 1280 2 0 {name=l_x99_out lab=net99}
C {lab_wire.sym} -450 1260 2 0 {name=l_x99_vdd lab=vdd}
C {lab_wire.sym} -450 1300 2 0 {name=l_x99_vss lab=vss}
C {sar_adc/blocks/async_sar/async_inverter.sym} -200 1280 0 0 {name=x100}
C {lab_wire.sym} -350 1260 0 0 {name=l_x100_in lab=net99}
C {lab_wire.sym} -50 1280 2 0 {name=l_x100_out lab=net100}
C {lab_wire.sym} -50 1260 2 0 {name=l_x100_vdd lab=vdd}
C {lab_wire.sym} -50 1300 2 0 {name=l_x100_vss lab=vss}
C {sar_adc/blocks/async_sar/async_inverter.sym} 200 1280 0 0 {name=x101}
C {lab_wire.sym} 50 1260 0 0 {name=l_x101_in lab=net100}
C {lab_wire.sym} 350 1280 2 0 {name=l_x101_out lab=net101}
C {lab_wire.sym} 350 1260 2 0 {name=l_x101_vdd lab=vdd}
C {lab_wire.sym} 350 1300 2 0 {name=l_x101_vss lab=vss}
C {sar_adc/blocks/async_sar/async_inverter.sym} 600 1280 0 0 {name=x102}
C {lab_wire.sym} 450 1260 0 0 {name=l_x102_in lab=net101}
C {lab_wire.sym} 750 1280 2 0 {name=l_x102_out lab=net102}
C {lab_wire.sym} 750 1260 2 0 {name=l_x102_vdd lab=vdd}
C {lab_wire.sym} 750 1300 2 0 {name=l_x102_vss lab=vss}
C {sar_adc/blocks/async_sar/async_inverter.sym} 1000 1280 0 0 {name=x103}
C {lab_wire.sym} 850 1260 0 0 {name=l_x103_in lab=net102}
C {lab_wire.sym} 1150 1280 2 0 {name=l_x103_out lab=net103}
C {lab_wire.sym} 1150 1260 2 0 {name=l_x103_vdd lab=vdd}
C {lab_wire.sym} 1150 1300 2 0 {name=l_x103_vss lab=vss}
C {sar_adc/blocks/async_sar/async_inverter.sym} 1400 1280 0 0 {name=x104}
C {lab_wire.sym} 1250 1260 0 0 {name=l_x104_in lab=net103}
C {lab_wire.sym} 1550 1280 2 0 {name=l_x104_out lab=net104}
C {lab_wire.sym} 1550 1260 2 0 {name=l_x104_vdd lab=vdd}
C {lab_wire.sym} 1550 1300 2 0 {name=l_x104_vss lab=vss}
C {sar_adc/blocks/async_sar/async_inverter.sym} -1400 1420 0 0 {name=x105}
C {lab_wire.sym} -1550 1400 0 0 {name=l_x105_in lab=net104}
C {lab_wire.sym} -1250 1420 2 0 {name=l_x105_out lab=net105}
C {lab_wire.sym} -1250 1400 2 0 {name=l_x105_vdd lab=vdd}
C {lab_wire.sym} -1250 1440 2 0 {name=l_x105_vss lab=vss}
C {sar_adc/blocks/async_sar/async_inverter.sym} -1000 1420 0 0 {name=x106}
C {lab_wire.sym} -1150 1400 0 0 {name=l_x106_in lab=net105}
C {lab_wire.sym} -850 1420 2 0 {name=l_x106_out lab=net106}
C {lab_wire.sym} -850 1400 2 0 {name=l_x106_vdd lab=vdd}
C {lab_wire.sym} -850 1440 2 0 {name=l_x106_vss lab=vss}
C {sar_adc/blocks/async_sar/async_inverter.sym} -600 1420 0 0 {name=x107}
C {lab_wire.sym} -750 1400 0 0 {name=l_x107_in lab=net106}
C {lab_wire.sym} -450 1420 2 0 {name=l_x107_out lab=net107}
C {lab_wire.sym} -450 1400 2 0 {name=l_x107_vdd lab=vdd}
C {lab_wire.sym} -450 1440 2 0 {name=l_x107_vss lab=vss}
C {sar_adc/blocks/async_sar/async_inverter.sym} -200 1420 0 0 {name=x108}
C {lab_wire.sym} -350 1400 0 0 {name=l_x108_in lab=net107}
C {lab_wire.sym} -50 1420 2 0 {name=l_x108_out lab=net108}
C {lab_wire.sym} -50 1400 2 0 {name=l_x108_vdd lab=vdd}
C {lab_wire.sym} -50 1440 2 0 {name=l_x108_vss lab=vss}
C {sar_adc/blocks/async_sar/async_inverter.sym} 200 1420 0 0 {name=x109}
C {lab_wire.sym} 50 1400 0 0 {name=l_x109_in lab=net108}
C {lab_wire.sym} 350 1420 2 0 {name=l_x109_out lab=net109}
C {lab_wire.sym} 350 1400 2 0 {name=l_x109_vdd lab=vdd}
C {lab_wire.sym} 350 1440 2 0 {name=l_x109_vss lab=vss}
C {sar_adc/blocks/async_sar/async_inverter.sym} 600 1420 0 0 {name=x110}
C {lab_wire.sym} 450 1400 0 0 {name=l_x110_in lab=net109}
C {lab_wire.sym} 750 1420 2 0 {name=l_x110_out lab=net110}
C {lab_wire.sym} 750 1400 2 0 {name=l_x110_vdd lab=vdd}
C {lab_wire.sym} 750 1440 2 0 {name=l_x110_vss lab=vss}
C {sar_adc/blocks/async_sar/async_inverter.sym} 1000 1420 0 0 {name=x111}
C {lab_wire.sym} 850 1400 0 0 {name=l_x111_in lab=net110}
C {lab_wire.sym} 1150 1420 2 0 {name=l_x111_out lab=net111}
C {lab_wire.sym} 1150 1400 2 0 {name=l_x111_vdd lab=vdd}
C {lab_wire.sym} 1150 1440 2 0 {name=l_x111_vss lab=vss}
C {sar_adc/blocks/async_sar/async_inverter.sym} 1400 1420 0 0 {name=x112}
C {lab_wire.sym} 1250 1400 0 0 {name=l_x112_in lab=net111}
C {lab_wire.sym} 1550 1420 2 0 {name=l_x112_out lab=net112}
C {lab_wire.sym} 1550 1400 2 0 {name=l_x112_vdd lab=vdd}
C {lab_wire.sym} 1550 1440 2 0 {name=l_x112_vss lab=vss}
C {sar_adc/blocks/async_sar/async_inverter.sym} -1400 1560 0 0 {name=x113}
C {lab_wire.sym} -1550 1540 0 0 {name=l_x113_in lab=net112}
C {lab_wire.sym} -1250 1560 2 0 {name=l_x113_out lab=net113}
C {lab_wire.sym} -1250 1540 2 0 {name=l_x113_vdd lab=vdd}
C {lab_wire.sym} -1250 1580 2 0 {name=l_x113_vss lab=vss}
C {sar_adc/blocks/async_sar/async_inverter.sym} -1000 1560 0 0 {name=x114}
C {lab_wire.sym} -1150 1540 0 0 {name=l_x114_in lab=net113}
C {lab_wire.sym} -850 1560 2 0 {name=l_x114_out lab=net114}
C {lab_wire.sym} -850 1540 2 0 {name=l_x114_vdd lab=vdd}
C {lab_wire.sym} -850 1580 2 0 {name=l_x114_vss lab=vss}
C {sar_adc/blocks/async_sar/async_inverter.sym} -600 1560 0 0 {name=x115}
C {lab_wire.sym} -750 1540 0 0 {name=l_x115_in lab=net114}
C {lab_wire.sym} -450 1560 2 0 {name=l_x115_out lab=net115}
C {lab_wire.sym} -450 1540 2 0 {name=l_x115_vdd lab=vdd}
C {lab_wire.sym} -450 1580 2 0 {name=l_x115_vss lab=vss}
C {sar_adc/blocks/async_sar/async_inverter.sym} -200 1560 0 0 {name=x116}
C {lab_wire.sym} -350 1540 0 0 {name=l_x116_in lab=net115}
C {lab_wire.sym} -50 1560 2 0 {name=l_x116_out lab=net116}
C {lab_wire.sym} -50 1540 2 0 {name=l_x116_vdd lab=vdd}
C {lab_wire.sym} -50 1580 2 0 {name=l_x116_vss lab=vss}
C {sar_adc/blocks/async_sar/async_inverter.sym} 200 1560 0 0 {name=x117}
C {lab_wire.sym} 50 1540 0 0 {name=l_x117_in lab=net116}
C {lab_wire.sym} 350 1560 2 0 {name=l_x117_out lab=net117}
C {lab_wire.sym} 350 1540 2 0 {name=l_x117_vdd lab=vdd}
C {lab_wire.sym} 350 1580 2 0 {name=l_x117_vss lab=vss}
C {sar_adc/blocks/async_sar/async_inverter.sym} 600 1560 0 0 {name=x118}
C {lab_wire.sym} 450 1540 0 0 {name=l_x118_in lab=net117}
C {lab_wire.sym} 750 1560 2 0 {name=l_x118_out lab=net118}
C {lab_wire.sym} 750 1540 2 0 {name=l_x118_vdd lab=vdd}
C {lab_wire.sym} 750 1580 2 0 {name=l_x118_vss lab=vss}
C {sar_adc/blocks/async_sar/async_inverter.sym} 1000 1560 0 0 {name=x119}
C {lab_wire.sym} 850 1540 0 0 {name=l_x119_in lab=net118}
C {lab_wire.sym} 1150 1560 2 0 {name=l_x119_out lab=net119}
C {lab_wire.sym} 1150 1540 2 0 {name=l_x119_vdd lab=vdd}
C {lab_wire.sym} 1150 1580 2 0 {name=l_x119_vss lab=vss}
C {sar_adc/blocks/async_sar/async_inverter.sym} 1400 1560 0 0 {name=x120}
C {lab_wire.sym} 1250 1540 0 0 {name=l_x120_in lab=net119}
C {lab_wire.sym} 1550 1560 2 0 {name=l_x120_out lab=net120}
C {lab_wire.sym} 1550 1540 2 0 {name=l_x120_vdd lab=vdd}
C {lab_wire.sym} 1550 1580 2 0 {name=l_x120_vss lab=vss}
C {sar_adc/blocks/async_sar/async_inverter.sym} -1400 1700 0 0 {name=x121}
C {lab_wire.sym} -1550 1680 0 0 {name=l_x121_in lab=net120}
C {lab_wire.sym} -1250 1700 2 0 {name=l_x121_out lab=net121}
C {lab_wire.sym} -1250 1680 2 0 {name=l_x121_vdd lab=vdd}
C {lab_wire.sym} -1250 1720 2 0 {name=l_x121_vss lab=vss}
C {sar_adc/blocks/async_sar/async_inverter.sym} -1000 1700 0 0 {name=x122}
C {lab_wire.sym} -1150 1680 0 0 {name=l_x122_in lab=net121}
C {lab_wire.sym} -850 1700 2 0 {name=l_x122_out lab=net122}
C {lab_wire.sym} -850 1680 2 0 {name=l_x122_vdd lab=vdd}
C {lab_wire.sym} -850 1720 2 0 {name=l_x122_vss lab=vss}
C {sar_adc/blocks/async_sar/async_inverter.sym} -600 1700 0 0 {name=x123}
C {lab_wire.sym} -750 1680 0 0 {name=l_x123_in lab=net122}
C {lab_wire.sym} -450 1700 2 0 {name=l_x123_out lab=net123}
C {lab_wire.sym} -450 1680 2 0 {name=l_x123_vdd lab=vdd}
C {lab_wire.sym} -450 1720 2 0 {name=l_x123_vss lab=vss}
C {sar_adc/blocks/async_sar/async_inverter.sym} -200 1700 0 0 {name=x124}
C {lab_wire.sym} -350 1680 0 0 {name=l_x124_in lab=net123}
C {lab_wire.sym} -50 1700 2 0 {name=l_x124_out lab=net124}
C {lab_wire.sym} -50 1680 2 0 {name=l_x124_vdd lab=vdd}
C {lab_wire.sym} -50 1720 2 0 {name=l_x124_vss lab=vss}
C {sar_adc/blocks/async_sar/async_inverter.sym} 200 1700 0 0 {name=x125}
C {lab_wire.sym} 50 1680 0 0 {name=l_x125_in lab=net124}
C {lab_wire.sym} 350 1700 2 0 {name=l_x125_out lab=net125}
C {lab_wire.sym} 350 1680 2 0 {name=l_x125_vdd lab=vdd}
C {lab_wire.sym} 350 1720 2 0 {name=l_x125_vss lab=vss}
C {sar_adc/blocks/async_sar/async_inverter.sym} 600 1700 0 0 {name=x126}
C {lab_wire.sym} 450 1680 0 0 {name=l_x126_in lab=net125}
C {lab_wire.sym} 750 1700 2 0 {name=l_x126_out lab=net126}
C {lab_wire.sym} 750 1680 2 0 {name=l_x126_vdd lab=vdd}
C {lab_wire.sym} 750 1720 2 0 {name=l_x126_vss lab=vss}
C {sar_adc/blocks/async_sar/async_inverter.sym} 1000 1700 0 0 {name=x127}
C {lab_wire.sym} 850 1680 0 0 {name=l_x127_in lab=net126}
C {lab_wire.sym} 1150 1700 2 0 {name=l_x127_out lab=net127}
C {lab_wire.sym} 1150 1680 2 0 {name=l_x127_vdd lab=vdd}
C {lab_wire.sym} 1150 1720 2 0 {name=l_x127_vss lab=vss}
C {sar_adc/blocks/async_sar/async_inverter.sym} 1400 1700 0 0 {name=x128}
C {lab_wire.sym} 1250 1680 0 0 {name=l_x128_in lab=net127}
C {lab_wire.sym} 1550 1700 2 0 {name=l_x128_out lab=net128}
C {lab_wire.sym} 1550 1680 2 0 {name=l_x128_vdd lab=vdd}
C {lab_wire.sym} 1550 1720 2 0 {name=l_x128_vss lab=vss}
C {sar_adc/blocks/async_sar/async_inverter.sym} -1400 1840 0 0 {name=x129}
C {lab_wire.sym} -1550 1820 0 0 {name=l_x129_in lab=net128}
C {lab_wire.sym} -1250 1840 2 0 {name=l_x129_out lab=net129}
C {lab_wire.sym} -1250 1820 2 0 {name=l_x129_vdd lab=vdd}
C {lab_wire.sym} -1250 1860 2 0 {name=l_x129_vss lab=vss}
C {sar_adc/blocks/async_sar/async_inverter.sym} -1000 1840 0 0 {name=x130}
C {lab_wire.sym} -1150 1820 0 0 {name=l_x130_in lab=net129}
C {lab_wire.sym} -850 1840 2 0 {name=l_x130_out lab=net130}
C {lab_wire.sym} -850 1820 2 0 {name=l_x130_vdd lab=vdd}
C {lab_wire.sym} -850 1860 2 0 {name=l_x130_vss lab=vss}
C {sar_adc/blocks/async_sar/async_inverter.sym} -600 1840 0 0 {name=x131}
C {lab_wire.sym} -750 1820 0 0 {name=l_x131_in lab=net130}
C {lab_wire.sym} -450 1840 2 0 {name=l_x131_out lab=net131}
C {lab_wire.sym} -450 1820 2 0 {name=l_x131_vdd lab=vdd}
C {lab_wire.sym} -450 1860 2 0 {name=l_x131_vss lab=vss}
C {sar_adc/blocks/async_sar/async_inverter.sym} -200 1840 0 0 {name=x132}
C {lab_wire.sym} -350 1820 0 0 {name=l_x132_in lab=net131}
C {lab_wire.sym} -50 1840 2 0 {name=l_x132_out lab=net132}
C {lab_wire.sym} -50 1820 2 0 {name=l_x132_vdd lab=vdd}
C {lab_wire.sym} -50 1860 2 0 {name=l_x132_vss lab=vss}
C {sar_adc/blocks/async_sar/async_inverter.sym} 200 1840 0 0 {name=x133}
C {lab_wire.sym} 50 1820 0 0 {name=l_x133_in lab=net132}
C {lab_wire.sym} 350 1840 2 0 {name=l_x133_out lab=net133}
C {lab_wire.sym} 350 1820 2 0 {name=l_x133_vdd lab=vdd}
C {lab_wire.sym} 350 1860 2 0 {name=l_x133_vss lab=vss}
C {sar_adc/blocks/async_sar/async_inverter.sym} 600 1840 0 0 {name=x134}
C {lab_wire.sym} 450 1820 0 0 {name=l_x134_in lab=net133}
C {lab_wire.sym} 750 1840 2 0 {name=l_x134_out lab=net134}
C {lab_wire.sym} 750 1820 2 0 {name=l_x134_vdd lab=vdd}
C {lab_wire.sym} 750 1860 2 0 {name=l_x134_vss lab=vss}
C {sar_adc/blocks/async_sar/async_inverter.sym} 1000 1840 0 0 {name=x135}
C {lab_wire.sym} 850 1820 0 0 {name=l_x135_in lab=net134}
C {lab_wire.sym} 1150 1840 2 0 {name=l_x135_out lab=out}
C {lab_wire.sym} 1150 1820 2 0 {name=l_x135_vdd lab=vdd}
C {lab_wire.sym} 1150 1860 2 0 {name=l_x135_vss lab=vss}
